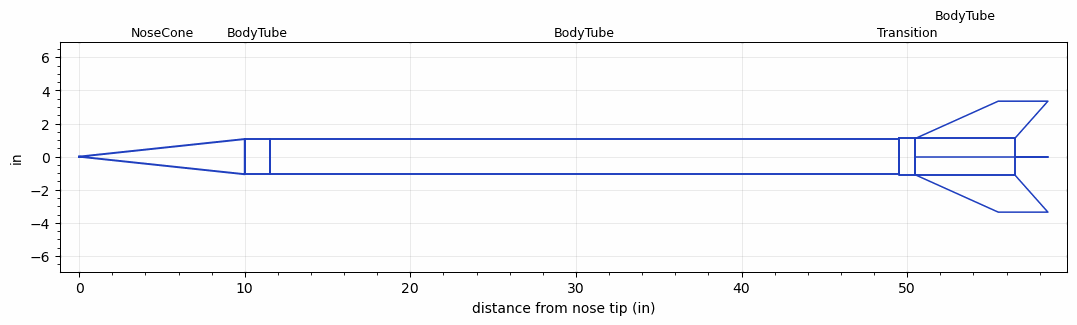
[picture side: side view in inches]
<RASAeroDocument>
 <FileVersion>2</FileVersion>
 <RocketDesign>
  <NoseCone>
   <Length>10</Length>
   <Diameter>2.125</Diameter>
   <Shape>Conical</Shape>
   <BluntRadius>0.0375</BluntRadius>
   <Location>0</Location>
  </NoseCone>
  <BodyTube>
   <Length>1.5</Length>
   <Diameter>2.125</Diameter>
   <Location>10</Location>
  </BodyTube>
  <BodyTube>
   <Length>37.9999</Length>
   <Diameter>2.125</Diameter>
   <Location>11.5</Location>
  </BodyTube>
  <Transition>
   <Length>1</Length>
   <Diameter>2.2</Diameter>
   <Location>49.4999</Location>
   <RearDiameter>2.2</RearDiameter>
  </Transition>
  <BodyTube>
   <Length>6</Length>
   <Diameter>2.2</Diameter>
   <Location>50.4999</Location>
   <Fin>
    <Count>4</Count>
    <Chord>6</Chord>
    <Span>2.25</Span>
    <SweepDistance>5</SweepDistance>
    <TipChord>3</TipChord>
    <Thickness>0.125</Thickness>
    <LERadius>0.01</LERadius>
    <Location>6</Location>
    <AirfoilSection>Double Wedge</AirfoilSection>
    <FX1>0.75</FX1>
   </Fin>
  </BodyTube>
  <Surface>Rough Camouflage Paint</Surface>
  <ModifiedBarrowman>True</ModifiedBarrowman>
  <Turbulence>True</Turbulence>
  <UseBooster1>False</UseBooster1>
  <UseBooster2>False</UseBooster2>
 </RocketDesign>
 <LaunchSite>
  <Altitude>2000</Altitude>
  <Pressure>27.8281</Pressure>
  <RodAngle>0</RodAngle>
  <RodLength>6</RodLength>
  <Temperature>51.8677</Temperature>
  <WindSpeed>4.4739</WindSpeed>
 </LaunchSite>
 <Recovery>
  <Altitude1>0</Altitude1>
  <Altitude2>0</Altitude2>
  <DeviceType1>None</DeviceType1>
  <DeviceType2>None</DeviceType2>
  <Event1>False</Event1>
  <Event2>False</Event2>
  <Size1>0</Size1>
  <Size2>0</Size2>
  <EventType1>None</EventType1>
  <EventType2>None</EventType2>
  <CD1>0</CD1>
  <CD2>0</CD2>
 </Recovery>
 <SimulationList>
  <Simulation>
   <SustainerEngine>M2091BPNC  (Polaris)</SustainerEngine>
   <SustainerLaunchWt>9.2</SustainerLaunchWt>
   <SustainerNozzleDiameter>2</SustainerNozzleDiameter>
   <SustainerCG>32.86</SustainerCG>
   <SustainerIgnitionDelay>0</SustainerIgnitionDelay>
   <Booster1SeparationDelay>0</Booster1SeparationDelay>
   <Booster1IgnitionDelay>0</Booster1IgnitionDelay>
   <IncludeBooster1>False</IncludeBooster1>
   <Booster2Delay>0</Booster2Delay>
   <IncludeBooster2>False</IncludeBooster2>
   <TimetoApogee>39.07945</TimetoApogee>
   <MaxAltitude>47463.8</MaxAltitude>
   <MaxVelocity>6022.72</MaxVelocity>
  </Simulation>
 </SimulationList>
</RASAeroDocument>
